VERSION 5.8 ;
BUSBITCHARS "[]" ;
DIVIDERCHAR "/" ;
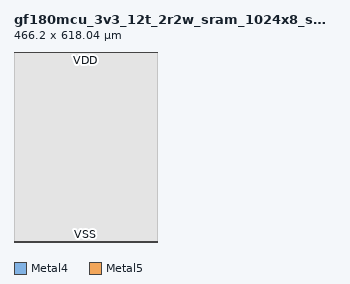
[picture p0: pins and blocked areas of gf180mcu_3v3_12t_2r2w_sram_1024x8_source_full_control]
MACRO gf180mcu_3v3_12t_2r2w_sram_1024x8_source_full_control
  CLASS BLOCK ;
  FOREIGN gf180mcu_3v3_12t_2r2w_sram_1024x8_source_full_control 0.000 0.000 ;
  ORIGIN 0.000 0.000 ;
  SIZE 466.200000 BY 618.040000 ;
  SYMMETRY X Y ;
  PIN VDD
    DIRECTION INOUT ;
    USE POWER ;
    PORT
      LAYER Metal4 ;
        RECT 0.000000 617.040000 466.200000 618.040000 ;
      LAYER Metal5 ;
        RECT 0.000000 617.040000 466.200000 618.040000 ;
    END
  END VDD
  PIN VSS
    DIRECTION INOUT ;
    USE GROUND ;
    PORT
      LAYER Metal4 ;
        RECT 0.000000 0.000000 466.200000 1.000000 ;
      LAYER Metal5 ;
        RECT 0.000000 0.000000 466.200000 1.000000 ;
    END
  END VSS
  OBS
    LAYER Metal1 ;
      RECT 0.000000 0.000000 466.200000 618.040000 ;
    LAYER Metal2 ;
      RECT 0.000000 0.000000 466.200000 618.040000 ;
    LAYER Metal3 ;
      RECT 0.000000 1.200000 466.200000 616.840000 ;
    LAYER Metal4 ;
      RECT 0.000000 1.200000 466.200000 616.840000 ;
    LAYER Metal5 ;
      RECT 0.000000 1.200000 466.200000 616.840000 ;
  END
END gf180mcu_3v3_12t_2r2w_sram_1024x8_source_full_control
END LIBRARY
